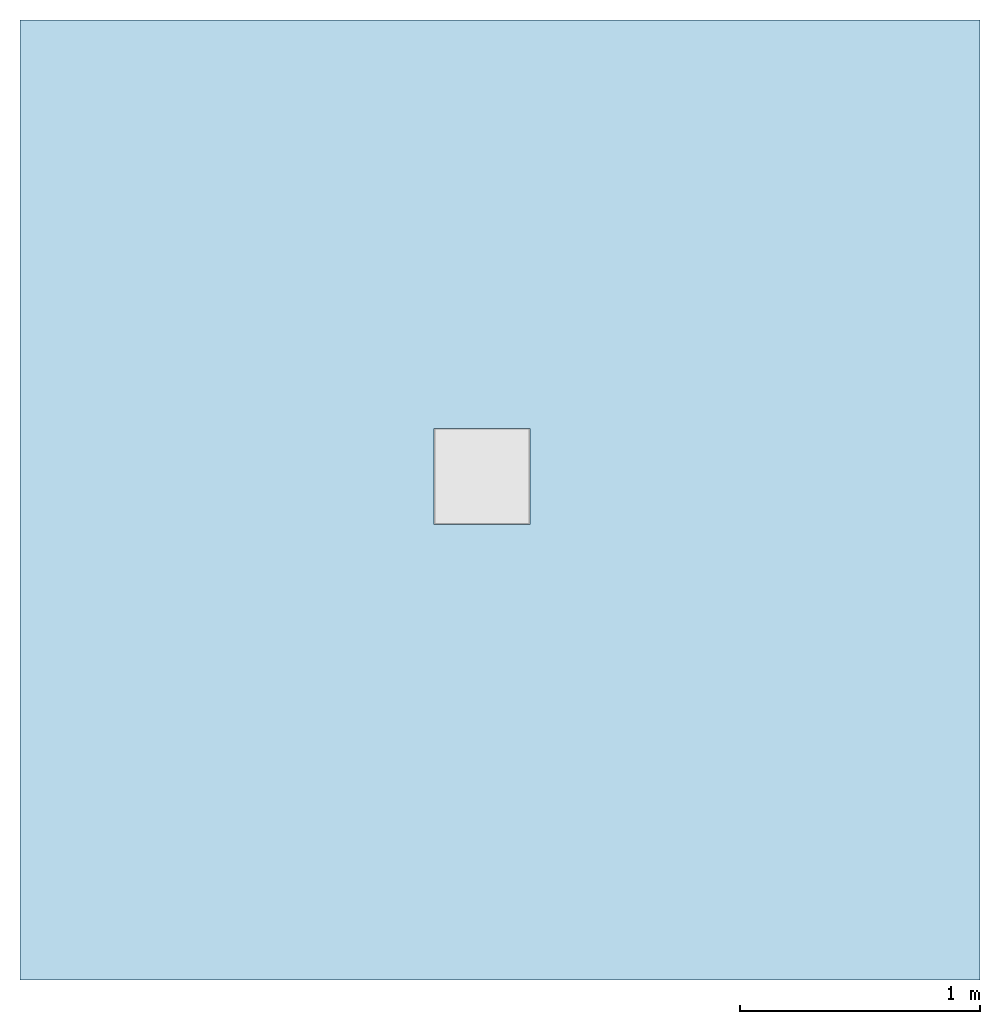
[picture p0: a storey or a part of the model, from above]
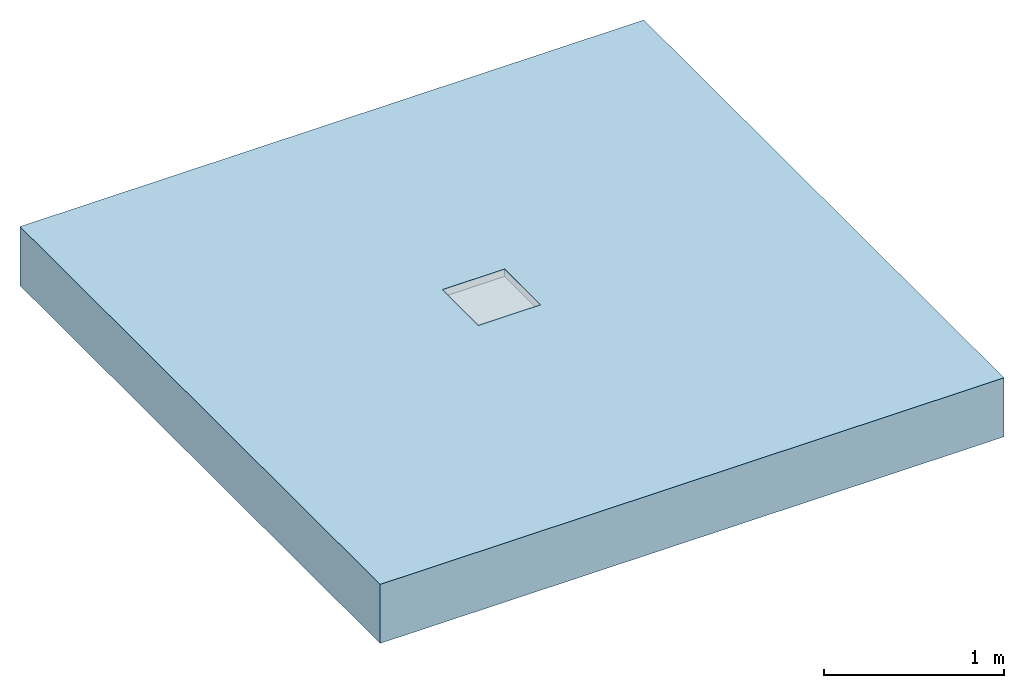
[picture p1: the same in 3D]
Properties of the parts of a building model (IFC2X3)

# File
Description: ViewDefinition [CoordinationView]
File name: Project Number
Time: 2014-06-06T11:10:24
Written by: The EXPRESS Data Manager Version 5.01.0100.02.64mod : 6 Jun 2012
Made in: 20130308_1515(x64) - Exporter 2014.0.2013.0308 - Default UI
Comment: STEP Physical File produced by: The EXPRESS Data Manager Version 5.01.0100.02.64mod : 6 Jun 2012 * Module: EDMstepFileFactory/EDMstandAlone * Creation date: Fri Jun 06 11:10:24 2014 * Host: IN-BLR-PC-0010 * Database: C:\Users\palleri\AppData\Local\Temp\{315EFC03-BEF5-41CE-9382-FCA54C3FE774}\ifc * Database version: 5507 * Database creation date: Fri Jun 06 11:10:23 2014 * Schema: IFC2X3 * Model: DataRepository.ifc * Model creation date: Fri Jun 06 11:10:23 2014 * Header model: DataRepository.ifc_HeaderModel * Header model creation date: Fri Jun 06 11:10:23 2014 * EDMuser: sdai-user * EDMgroup: sdai-group * License ID and type: 5605 : Permanent license. Expiry date: * EDMstepFileFactory options: 020000

# IfcProject, Project Number
LongName: Project Name; Phase: Project Status

# IfcSite, Default
RefLatitude: 42, 21, 30, 344238; RefLongitude: -71, -3, -35, -194702; RefElevation: 0 mm

# IfcBuilding
Pset_BuildingCommon - NumberOfStoreys: 1
Other - Project Status: Project Status; Project Address: ## Street City, State Zip; Project Number: Project Number; Project Issue Date: Issue Date; Client Name: Owner; Project Name: Project Name

# IfcBuildingStorey, Level 1
LongName: Level 1; Elevation: 0 mm
Graphics - Symbol at End 1 Default: no; Line Pattern: Center; Color: 0; Symbol: M_Level Head - Circle: M_Level Head - Circle; Line Weight: 1; Symbol at End 2 Default: yes
Constraints - Elevation Base: Project Base Point; Elevation: 0 mm
Identity Data - Building Story: yes; Name: Level 1; Structural: no
Dimensions - Computation Height: 0 mm

# IfcFlowTerminal: 38156 - Access Frame - Fixed Height - Invert Depth 50mm, ACO Freedeck Access Frame & Drain Duct (Accessories part 1) V1.27 - SS:38156 - Access Frame - Fixed Height - Invert Depth 50mm:278221
In: Level 1
Material: Stainless Steel Grade 304
Other - Drain Duct Vertical Height: 5000 mm; Access Frame Extension: no; Access Frame Extension_Invert Depth 50mm: no; Access Frame Extension Height: 50 mm; Access Frame Extension_Invert Depth 75mm: no; Fixed Access Frame Position Height: 50 mm; Extension Removal Void: -2 mm; Adjustable Access Frame Position Height: 105 mm; Top void Size: 400 mm; Access Frame Adjustable Height: no; Grating: yes; Access Frame Fixed Height: yes; Drain Duct: no
Phasing - Phase Created: New Construction
Dimensions - Drainage Duct – Level below FFL: 30 mm; Base Height: 3000 mm; Top Void Height End: -50 mm; Total Height: 105 mm; Access Frame Extension Position Height: 5000 mm; Height for Adjustable Access Frame: 105 mm; Top Void Height Start: 2 mm; Grating Start: 0 mm; Grating End: -20 mm; Drain Duct End: -100 mm
Construction - 38688_Access Frame Extension_Stainless Steel_Invert Depth 75mm: no; 36760_Access Grating_Mesh Grating_Stainless Steel 304: yes; 38686_Access Frame Extension_Stainless Steel_Invert Depth 50mm: no
Constraints - Moves With Nearby Elements: no; Level: Level: Level 1
Identity Data - Mark: 15; Watermark1: This file is the property of ACO Technologies PLC; Address: ACO Business Centre, Caxton Road, Bedford, MK41 0LF; Watermarked With: BIM Manager Premium Suite; Watermark2: This file is water marked and users are prohibited to reproduce, adapt, distribute this information; Website: www.acobd.com; Fax: +44 (0)1462 851490; E-mail Technical: abdtechnical@aco.co.uk; Telephone: +44 (0)1462 816666; Manufacturer: ACO Building Drainage; Watermarked By: www.acobd.com; E-mail Sales: abdcommercial@aco.co.uk
Pset_ManufacturerTypeInformation - Manufacturer: ACO Building Drainage
General - Product Standard: BS EN 1433:2002, CE marked; Product Code: 38156; Product Type: Linear Deck Drainage System; Product Range: ACO Freedeck; Channel Recyclable: Fully recyclable; Product Description: ACO Freedeck Access Frame - Fixed Height; Channel Colour: Mid Grey; Weight (Kg): 5.7kg; Dimensions (LxWxH): 400 x 400 x 50; Maintenance Guidelines: X:\Electronic Literature\ABD Electronic Literature\Roof and Balcony Drainage\ACO Freedeck Brochure.pdf; NBS Specification: NBS Section R10 Gravity Rainwater Drainage Systems, Subsection 365; Channel Recycled Material Content: 60 - 70 %; Channel Material: Stainless Steel Grade 304; Price: POA - contact ACO; Installation Guidelines: X:\Electronic Literature\ABD Electronic Literature\Roof and Balcony Drainage\ACO Freedeck Brochure.pdf; Load Class: A15
Materials and Finishes - Material: Stainless Steel Grade 304
Model Properties - Access Frame Extension Product Code 38687: N/A; Access Frame Extension Product Code 38686: Load Class A15 - Access Frame Extension - Stainless Steel 304 - Invert Depth 50mm - 1.3kg; Access Frame Extension Product Code 38688: Load Class A15 - Access Frame Extension - Stainless Steel 304 - Invert Depth 75mm - 1.9kg; Access Frame Extension Product Code 38685: N/A; Access Grating Product Code 36760: Load Class A15 - Mesh Grating - 14mm x 30mm Mesh - Stainless Steel 304 - 3.5kg; Access Grating Product Code 36754: N/A

# IfcSlab: Floor:Generic Floor - 400mm, Floor:Generic Floor - 400mm:193825
In: Level 1
PredefinedType: FLOOR; Material: Concrete, Broom Finish 400 mm
Dimensions - Thickness: 400 mm; Volume: 6.392 m3; Area: 16 m2; Perimeter: 16000 mm
Constraints - Room Bounding: yes; Related to Mass: no; Height Offset From Level: 0 mm; Level: Level: Level 1
Phasing - Phase Created: New Construction
Structural - Structural: no; Enable Analytical Model: no
Pset_SlabCommon - Reference: Generic Floor - 400mm; IsExternal: no; LoadBearing: yes; ThermalTransmittance: 2.615 kg/K/s3; PitchAngle: 0 deg
Construction - Default Thickness: 400 mm; Function: Interior
Analytical Properties - Heat Transfer Coefficient (U): 2.615; Absorptance: 0.1; Roughness: 1; Thermal mass: 604440; Thermal Resistance (R): 0.382409
Materials and Finishes - Structural Material: Concrete, Broom Finish
Graphics - Coarse Scale Fill Color: 0
